VERSION 5.8 ;
BUSBITCHARS "[]" ;
DIVIDERCHAR "/" ;
UNITS
    DATABASE MICRONS 1000 ;
END UNITS

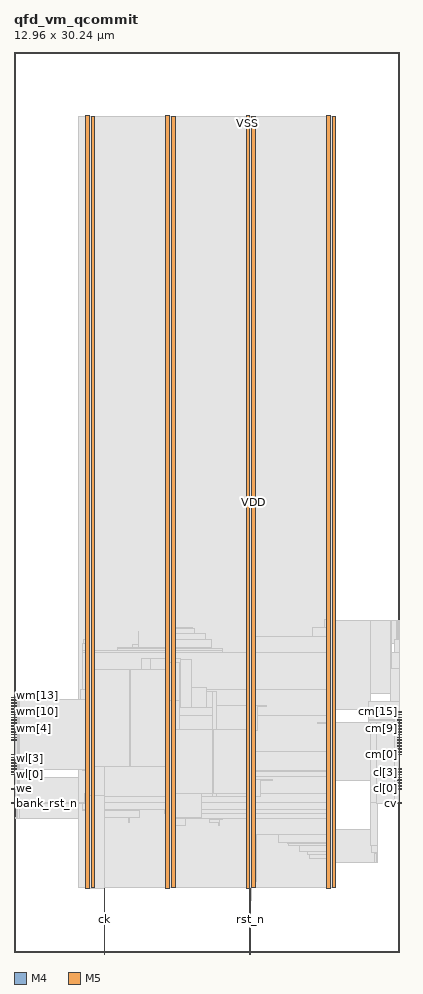
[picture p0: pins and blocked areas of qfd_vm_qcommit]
MACRO qfd_vm_qcommit
  FOREIGN qfd_vm_qcommit 0 0 ;
  CLASS BLOCK ;
  SIZE 12.96 BY 30.24 ;
  PIN bank_rst_n
    DIRECTION INPUT ;
    USE SIGNAL ;
    PORT
      LAYER M4 ;
        RECT  -0.072 4.992 0.072 5.016 ;
    END
  END bank_rst_n
  PIN ck
    DIRECTION INPUT ;
    USE SIGNAL ;
    PORT
      LAYER M5 ;
        RECT  3.024 -0.072 3.048 0.072 ;
    END
    PORT
      LAYER M5 ;
        RECT  3.024 0.016 3.048 2.137 ;
    END
  END ck
  PIN cl[0]
    DIRECTION OUTPUT ;
    USE SIGNAL ;
    PORT
      LAYER M4 ;
        RECT  12.888 5.472 13.032 5.496 ;
    END
  END cl[0]
  PIN cl[1]
    DIRECTION OUTPUT ;
    USE SIGNAL ;
    PORT
      LAYER M4 ;
        RECT  12.888 5.568 13.032 5.592 ;
    END
  END cl[1]
  PIN cl[2]
    DIRECTION OUTPUT ;
    USE SIGNAL ;
    PORT
      LAYER M4 ;
        RECT  12.888 5.664 13.032 5.688 ;
    END
  END cl[2]
  PIN cl[3]
    DIRECTION OUTPUT ;
    USE SIGNAL ;
    PORT
      LAYER M4 ;
        RECT  12.888 5.76 13.032 5.784 ;
    END
  END cl[3]
  PIN cl[4]
    DIRECTION OUTPUT ;
    USE SIGNAL ;
    PORT
      LAYER M4 ;
        RECT  12.888 5.856 13.032 5.88 ;
    END
  END cl[4]
  PIN cl[5]
    DIRECTION OUTPUT ;
    USE SIGNAL ;
    PORT
      LAYER M4 ;
        RECT  12.888 5.952 13.032 5.976 ;
    END
  END cl[5]
  PIN cl[6]
    DIRECTION OUTPUT ;
    USE SIGNAL ;
    PORT
      LAYER M4 ;
        RECT  12.888 6.048 13.032 6.072 ;
    END
  END cl[6]
  PIN cl[7]
    DIRECTION OUTPUT ;
    USE SIGNAL ;
    PORT
      LAYER M4 ;
        RECT  12.888 6.144 13.032 6.168 ;
    END
  END cl[7]
  PIN cm[0]
    DIRECTION OUTPUT ;
    USE SIGNAL ;
    PORT
      LAYER M4 ;
        RECT  12.888 6.624 13.032 6.648 ;
    END
  END cm[0]
  PIN cm[10]
    DIRECTION OUTPUT ;
    USE SIGNAL ;
    PORT
      LAYER M4 ;
        RECT  12.888 7.584 13.032 7.608 ;
    END
  END cm[10]
  PIN cm[11]
    DIRECTION OUTPUT ;
    USE SIGNAL ;
    PORT
      LAYER M4 ;
        RECT  12.888 7.68 13.032 7.704 ;
    END
  END cm[11]
  PIN cm[12]
    DIRECTION OUTPUT ;
    USE SIGNAL ;
    PORT
      LAYER M4 ;
        RECT  12.888 7.776 13.032 7.8 ;
    END
  END cm[12]
  PIN cm[13]
    DIRECTION OUTPUT ;
    USE SIGNAL ;
    PORT
      LAYER M4 ;
        RECT  12.888 7.872 13.032 7.896 ;
    END
  END cm[13]
  PIN cm[14]
    DIRECTION OUTPUT ;
    USE SIGNAL ;
    PORT
      LAYER M4 ;
        RECT  12.888 7.968 13.032 7.992 ;
    END
  END cm[14]
  PIN cm[15]
    DIRECTION OUTPUT ;
    USE SIGNAL ;
    PORT
      LAYER M4 ;
        RECT  12.888 8.064 13.032 8.088 ;
    END
  END cm[15]
  PIN cm[1]
    DIRECTION OUTPUT ;
    USE SIGNAL ;
    PORT
      LAYER M4 ;
        RECT  12.888 6.72 13.032 6.744 ;
    END
  END cm[1]
  PIN cm[2]
    DIRECTION OUTPUT ;
    USE SIGNAL ;
    PORT
      LAYER M4 ;
        RECT  12.888 6.816 13.032 6.84 ;
    END
  END cm[2]
  PIN cm[3]
    DIRECTION OUTPUT ;
    USE SIGNAL ;
    PORT
      LAYER M4 ;
        RECT  12.888 6.912 13.032 6.936 ;
    END
  END cm[3]
  PIN cm[4]
    DIRECTION OUTPUT ;
    USE SIGNAL ;
    PORT
      LAYER M4 ;
        RECT  12.888 7.008 13.032 7.032 ;
    END
  END cm[4]
  PIN cm[5]
    DIRECTION OUTPUT ;
    USE SIGNAL ;
    PORT
      LAYER M4 ;
        RECT  12.888 7.104 13.032 7.128 ;
    END
  END cm[5]
  PIN cm[6]
    DIRECTION OUTPUT ;
    USE SIGNAL ;
    PORT
      LAYER M4 ;
        RECT  12.888 7.2 13.032 7.224 ;
    END
  END cm[6]
  PIN cm[7]
    DIRECTION OUTPUT ;
    USE SIGNAL ;
    PORT
      LAYER M4 ;
        RECT  12.888 7.296 13.032 7.32 ;
    END
  END cm[7]
  PIN cm[8]
    DIRECTION OUTPUT ;
    USE SIGNAL ;
    PORT
      LAYER M4 ;
        RECT  12.888 7.392 13.032 7.416 ;
    END
  END cm[8]
  PIN cm[9]
    DIRECTION OUTPUT ;
    USE SIGNAL ;
    PORT
      LAYER M4 ;
        RECT  12.888 7.488 13.032 7.512 ;
    END
  END cm[9]
  PIN cv
    DIRECTION OUTPUT ;
    USE SIGNAL ;
    PORT
      LAYER M4 ;
        RECT  12.888 4.992 13.032 5.016 ;
    END
  END cv
  PIN rst_n
    DIRECTION INPUT ;
    USE SIGNAL ;
    PORT
      LAYER M5 ;
        RECT  7.92 -0.072 7.944 0.072 ;
    END
    PORT
      LAYER M5 ;
        RECT  7.92 0.016 7.944 2.137 ;
    END
  END rst_n
  PIN we
    DIRECTION INPUT ;
    USE SIGNAL ;
    PORT
      LAYER M4 ;
        RECT  -0.072 5.472 0.072 5.496 ;
    END
  END we
  PIN wl[0]
    DIRECTION INPUT ;
    USE SIGNAL ;
    PORT
      LAYER M4 ;
        RECT  -0.072 5.952 0.072 5.976 ;
    END
  END wl[0]
  PIN wl[1]
    DIRECTION INPUT ;
    USE SIGNAL ;
    PORT
      LAYER M4 ;
        RECT  -0.072 6.048 0.072 6.072 ;
    END
  END wl[1]
  PIN wl[2]
    DIRECTION INPUT ;
    USE SIGNAL ;
    PORT
      LAYER M4 ;
        RECT  -0.072 6.144 0.072 6.168 ;
    END
  END wl[2]
  PIN wl[3]
    DIRECTION INPUT ;
    USE SIGNAL ;
    PORT
      LAYER M4 ;
        RECT  -0.072 6.24 0.072 6.264 ;
    END
  END wl[3]
  PIN wl[4]
    DIRECTION INPUT ;
    USE SIGNAL ;
    PORT
      LAYER M4 ;
        RECT  -0.072 6.336 0.072 6.36 ;
    END
  END wl[4]
  PIN wl[5]
    DIRECTION INPUT ;
    USE SIGNAL ;
    PORT
      LAYER M4 ;
        RECT  -0.072 6.432 0.072 6.456 ;
    END
  END wl[5]
  PIN wl[6]
    DIRECTION INPUT ;
    USE SIGNAL ;
    PORT
      LAYER M4 ;
        RECT  -0.072 6.528 0.072 6.552 ;
    END
  END wl[6]
  PIN wl[7]
    DIRECTION INPUT ;
    USE SIGNAL ;
    PORT
      LAYER M4 ;
        RECT  -0.072 6.624 0.072 6.648 ;
    END
  END wl[7]
  PIN wm[0]
    DIRECTION INPUT ;
    USE SIGNAL ;
    PORT
      LAYER M4 ;
        RECT  -0.072 7.104 0.072 7.128 ;
    END
  END wm[0]
  PIN wm[10]
    DIRECTION INPUT ;
    USE SIGNAL ;
    PORT
      LAYER M4 ;
        RECT  -0.072 8.064 0.072 8.088 ;
    END
  END wm[10]
  PIN wm[11]
    DIRECTION INPUT ;
    USE SIGNAL ;
    PORT
      LAYER M4 ;
        RECT  -0.072 8.16 0.072 8.184 ;
    END
  END wm[11]
  PIN wm[12]
    DIRECTION INPUT ;
    USE SIGNAL ;
    PORT
      LAYER M4 ;
        RECT  -0.072 8.256 0.072 8.28 ;
    END
  END wm[12]
  PIN wm[13]
    DIRECTION INPUT ;
    USE SIGNAL ;
    PORT
      LAYER M4 ;
        RECT  -0.072 8.352 0.072 8.376 ;
    END
  END wm[13]
  PIN wm[14]
    DIRECTION INPUT ;
    USE SIGNAL ;
    PORT
      LAYER M4 ;
        RECT  -0.072 8.448 0.072 8.472 ;
    END
  END wm[14]
  PIN wm[15]
    DIRECTION INPUT ;
    USE SIGNAL ;
    PORT
      LAYER M4 ;
        RECT  -0.072 8.544 0.072 8.568 ;
    END
  END wm[15]
  PIN wm[1]
    DIRECTION INPUT ;
    USE SIGNAL ;
    PORT
      LAYER M4 ;
        RECT  -0.072 7.2 0.072 7.224 ;
    END
  END wm[1]
  PIN wm[2]
    DIRECTION INPUT ;
    USE SIGNAL ;
    PORT
      LAYER M4 ;
        RECT  -0.072 7.296 0.072 7.32 ;
    END
  END wm[2]
  PIN wm[3]
    DIRECTION INPUT ;
    USE SIGNAL ;
    PORT
      LAYER M4 ;
        RECT  -0.072 7.392 0.072 7.416 ;
    END
  END wm[3]
  PIN wm[4]
    DIRECTION INPUT ;
    USE SIGNAL ;
    PORT
      LAYER M4 ;
        RECT  -0.072 7.488 0.072 7.512 ;
    END
  END wm[4]
  PIN wm[5]
    DIRECTION INPUT ;
    USE SIGNAL ;
    PORT
      LAYER M4 ;
        RECT  -0.072 7.584 0.072 7.608 ;
    END
  END wm[5]
  PIN wm[6]
    DIRECTION INPUT ;
    USE SIGNAL ;
    PORT
      LAYER M4 ;
        RECT  -0.072 7.68 0.072 7.704 ;
    END
  END wm[6]
  PIN wm[7]
    DIRECTION INPUT ;
    USE SIGNAL ;
    PORT
      LAYER M4 ;
        RECT  -0.072 7.776 0.072 7.8 ;
    END
  END wm[7]
  PIN wm[8]
    DIRECTION INPUT ;
    USE SIGNAL ;
    PORT
      LAYER M4 ;
        RECT  -0.072 7.872 0.072 7.896 ;
    END
  END wm[8]
  PIN wm[9]
    DIRECTION INPUT ;
    USE SIGNAL ;
    PORT
      LAYER M4 ;
        RECT  -0.072 7.968 0.072 7.992 ;
    END
  END wm[9]
  PIN VDD
    DIRECTION INOUT ;
    USE POWER ;
    PORT
      LAYER M5 ;
        RECT  10.692 2.151 10.812 28.089 ;
        RECT  7.992 2.151 8.112 28.089 ;
        RECT  5.292 2.151 5.412 28.089 ;
        RECT  2.592 2.151 2.712 28.089 ;
    END
  END VDD
  PIN VSS
    DIRECTION INOUT ;
    USE GROUND ;
    PORT
      LAYER M5 ;
        RECT  10.5 2.137 10.62 28.103 ;
        RECT  7.8 2.137 7.92 28.103 ;
        RECT  5.1 2.137 5.22 28.103 ;
        RECT  2.4 2.137 2.52 28.103 ;
    END
  END VSS
  # OT_OBS_CLOSED layer=M5 d_um=1.536 added=6
  OBS
    LAYER RVTN ;
     RECT  2.16 2.16 10.8 2.295 ;
     RECT  2.16 2.565 10.8 2.835 ;
     RECT  2.16 3.105 10.8 3.375 ;
     RECT  2.16 3.645 10.8 3.915 ;
     RECT  2.16 4.185 10.8 4.455 ;
     RECT  2.16 4.725 10.8 4.995 ;
     RECT  2.16 5.265 10.8 5.535 ;
     RECT  2.16 5.805 10.8 6.075 ;
     RECT  2.16 6.345 10.8 6.615 ;
     RECT  2.16 6.885 10.8 7.155 ;
     RECT  2.16 7.425 10.8 7.695 ;
     RECT  2.16 7.965 10.8 8.235 ;
     RECT  2.16 8.505 10.8 8.775 ;
     RECT  2.16 9.045 10.8 9.315 ;
     RECT  2.16 9.585 10.8 9.855 ;
     RECT  2.16 10.125 10.8 10.395 ;
     RECT  2.16 10.665 10.8 10.935 ;
     RECT  2.16 11.205 10.8 11.475 ;
     RECT  2.16 11.745 10.8 12.015 ;
     RECT  2.16 12.285 10.8 12.555 ;
     RECT  2.16 12.825 10.8 13.095 ;
     RECT  2.16 13.365 10.8 13.635 ;
     RECT  2.16 13.905 10.8 14.175 ;
     RECT  2.16 14.445 10.8 14.715 ;
     RECT  2.16 14.985 10.8 15.255 ;
     RECT  2.16 15.525 10.8 15.795 ;
     RECT  2.16 16.065 10.8 16.335 ;
     RECT  2.16 16.605 10.8 16.875 ;
     RECT  2.16 17.145 10.8 17.415 ;
     RECT  2.16 17.685 10.8 17.955 ;
     RECT  2.16 18.225 10.8 18.495 ;
     RECT  2.16 18.765 10.8 19.035 ;
     RECT  2.16 19.305 10.8 19.575 ;
     RECT  2.16 19.845 10.8 20.115 ;
     RECT  2.16 20.385 10.8 20.655 ;
     RECT  2.16 20.925 10.8 21.195 ;
     RECT  2.16 21.465 10.8 21.735 ;
     RECT  2.16 22.005 10.8 22.275 ;
     RECT  2.16 22.545 10.8 22.815 ;
     RECT  2.16 23.085 10.8 23.355 ;
     RECT  2.16 23.625 10.8 23.895 ;
     RECT  2.16 24.165 10.8 24.435 ;
     RECT  2.16 24.705 10.8 24.975 ;
     RECT  2.16 25.245 10.8 25.515 ;
     RECT  2.16 25.785 10.8 26.055 ;
     RECT  2.16 26.325 10.8 26.595 ;
     RECT  2.16 26.865 10.8 27.135 ;
     RECT  2.16 27.405 10.8 27.675 ;
     RECT  2.16 27.945 10.8 28.08 ;
    LAYER RVTP ;
     RECT  2.16 2.295 10.8 2.565 ;
     RECT  2.16 2.835 10.8 3.105 ;
     RECT  2.16 3.375 10.8 3.645 ;
     RECT  2.16 3.915 10.8 4.185 ;
     RECT  2.16 4.455 10.8 4.725 ;
     RECT  2.16 4.995 10.8 5.265 ;
     RECT  2.16 5.535 10.8 5.805 ;
     RECT  2.16 6.075 10.8 6.345 ;
     RECT  2.16 6.615 10.8 6.885 ;
     RECT  2.16 7.155 10.8 7.425 ;
     RECT  2.16 7.695 10.8 7.965 ;
     RECT  2.16 8.235 10.8 8.505 ;
     RECT  2.16 8.775 10.8 9.045 ;
     RECT  2.16 9.315 10.8 9.585 ;
     RECT  2.16 9.855 10.8 10.125 ;
     RECT  2.16 10.395 10.8 10.665 ;
     RECT  2.16 10.935 10.8 11.205 ;
     RECT  2.16 11.475 10.8 11.745 ;
     RECT  2.16 12.015 10.8 12.285 ;
     RECT  2.16 12.555 10.8 12.825 ;
     RECT  2.16 13.095 10.8 13.365 ;
     RECT  2.16 13.635 10.8 13.905 ;
     RECT  2.16 14.175 10.8 14.445 ;
     RECT  2.16 14.715 10.8 14.985 ;
     RECT  2.16 15.255 10.8 15.525 ;
     RECT  2.16 15.795 10.8 16.065 ;
     RECT  2.16 16.335 10.8 16.605 ;
     RECT  2.16 16.875 10.8 17.145 ;
     RECT  2.16 17.415 10.8 17.685 ;
     RECT  2.16 17.955 10.8 18.225 ;
     RECT  2.16 18.495 10.8 18.765 ;
     RECT  2.16 19.035 10.8 19.305 ;
     RECT  2.16 19.575 10.8 19.845 ;
     RECT  2.16 20.115 10.8 20.385 ;
     RECT  2.16 20.655 10.8 20.925 ;
     RECT  2.16 21.195 10.8 21.465 ;
     RECT  2.16 21.735 10.8 22.005 ;
     RECT  2.16 22.275 10.8 22.545 ;
     RECT  2.16 22.815 10.8 23.085 ;
     RECT  2.16 23.355 10.8 23.625 ;
     RECT  2.16 23.895 10.8 24.165 ;
     RECT  2.16 24.435 10.8 24.705 ;
     RECT  2.16 24.975 10.8 25.245 ;
     RECT  2.16 25.515 10.8 25.785 ;
     RECT  2.16 26.055 10.8 26.325 ;
     RECT  2.16 26.595 10.8 26.865 ;
     RECT  2.16 27.135 10.8 27.405 ;
     RECT  2.16 27.675 10.8 27.945 ;
    LAYER M1 ;
     RECT  2.16 2.151 10.8 28.089 ;
    LAYER M2 ;
     RECT  0.067 4.5 0.103 4.518 ;
     RECT  0.067 5.58 0.103 5.598 ;
     RECT  0.067 6.822 0.103 6.84 ;
     RECT  0.103 4.5 0.175 5.598 ;
     RECT  0.175 4.5 2.16 5.868 ;
     RECT  0.103 6.822 2.16 7.416 ;
     RECT  0.067 8.442 2.16 8.46 ;
     RECT  2.16 2.151 10.8 28.089 ;
     RECT  10.8 2.421 10.812 27.819 ;
     RECT  10.812 5.886 11.435 7.344 ;
     RECT  11.435 5.976 11.975 7.344 ;
     RECT  10.812 8.136 11.975 11.124 ;
     RECT  11.975 5.976 12.011 6.714 ;
     RECT  12.011 6.552 12.083 6.714 ;
     RECT  10.812 3.006 12.119 4.104 ;
     RECT  12.119 4.086 12.155 4.104 ;
     RECT  12.119 3.006 12.191 3.294 ;
     RECT  12.191 3.006 12.227 3.024 ;
     RECT  11.975 8.676 12.659 11.124 ;
     RECT  12.659 10.026 12.695 11.124 ;
     RECT  12.659 8.676 12.731 8.964 ;
     RECT  12.731 8.946 12.767 8.964 ;
     RECT  12.695 10.368 12.839 11.124 ;
     RECT  12.839 10.44 12.875 11.124 ;
     RECT  12.847 7.821 12.947 7.839 ;
     RECT  12.875 11.106 12.947 11.124 ;
    LAYER M3 ;
     RECT  7.956 1.723 7.974 2.143 ;
     RECT  7.815 2.143 7.974 2.371 ;
     RECT  2.415 2.143 2.505 2.413 ;
     RECT  5.115 2.143 5.205 2.413 ;
     RECT  10.515 2.143 10.605 2.413 ;
     RECT  10.515 2.413 10.797 3.145 ;
     RECT  9.936 3.145 10.797 3.271 ;
     RECT  12.204 3.001 12.222 3.271 ;
     RECT  12.168 3.271 12.222 3.343 ;
     RECT  9.864 3.271 10.797 3.379 ;
     RECT  9.576 3.379 10.797 3.577 ;
     RECT  12.024 3.343 12.222 3.577 ;
     RECT  9.216 3.577 10.797 3.649 ;
     RECT  9.18 3.649 10.797 3.685 ;
     RECT  7.815 2.371 8.154 3.955 ;
     RECT  8.892 3.685 10.797 3.955 ;
     RECT  5.115 2.413 5.397 4.261 ;
     RECT  6.876 4.261 6.894 4.351 ;
     RECT  6.552 4.351 6.894 4.459 ;
     RECT  5.115 4.261 5.778 4.495 ;
     RECT  6.552 4.459 7.002 4.495 ;
     RECT  7.815 3.955 10.797 4.495 ;
     RECT  2.415 2.413 2.697 4.531 ;
     RECT  3.852 4.351 3.87 4.531 ;
     RECT  5.115 4.495 10.797 4.657 ;
     RECT  2.415 4.531 4.23 4.765 ;
     RECT  2.304 4.765 4.23 4.801 ;
     RECT  5.04 4.657 10.797 4.801 ;
     RECT  2.304 4.801 10.797 5.021 ;
     RECT  11.988 3.577 12.222 5.021 ;
     RECT  0.072 4.495 0.09 5.035 ;
     RECT  2.376 5.021 10.797 5.333 ;
     RECT  0.072 5.035 0.162 5.845 ;
     RECT  2.415 5.333 10.797 5.881 ;
     RECT  11.988 5.021 12.186 5.881 ;
     RECT  2.415 5.881 12.186 6.077 ;
     RECT  2.415 6.077 12.078 6.115 ;
     RECT  0.072 5.845 0.198 6.557 ;
     RECT  2.304 6.115 12.078 6.749 ;
     RECT  11.916 6.749 12.078 7.099 ;
     RECT  0.072 6.557 0.09 7.393 ;
     RECT  0.072 7.393 0.126 7.421 ;
     RECT  0.108 7.421 0.126 7.613 ;
     RECT  11.916 7.099 12.762 7.771 ;
     RECT  11.916 7.771 12.87 7.816 ;
     RECT  2.304 6.749 10.797 7.963 ;
     RECT  11.916 7.816 12.942 8.429 ;
     RECT  0.072 8.437 0.09 8.573 ;
     RECT  2.232 7.963 10.797 8.807 ;
     RECT  12.636 8.429 12.942 9.509 ;
     RECT  2.304 8.807 10.797 10.049 ;
     RECT  12.672 9.509 12.942 10.049 ;
     RECT  2.304 10.049 7.002 10.121 ;
     RECT  3.492 10.121 7.002 10.193 ;
     RECT  3.492 10.193 6.642 10.229 ;
     RECT  3.996 10.229 4.194 10.319 ;
     RECT  2.304 10.121 2.697 10.355 ;
     RECT  2.34 10.355 2.697 10.499 ;
     RECT  5.115 10.229 6.642 10.499 ;
     RECT  12.78 10.049 12.942 10.499 ;
     RECT  7.815 10.049 10.797 10.589 ;
     RECT  5.115 10.499 6.426 10.697 ;
     RECT  4.176 10.319 4.194 10.769 ;
     RECT  5.115 10.697 6.066 10.859 ;
     RECT  5.115 10.859 5.994 10.895 ;
     RECT  10.044 10.589 10.797 10.895 ;
     RECT  12.924 10.499 12.942 11.129 ;
     RECT  10.44 10.895 10.797 11.165 ;
     RECT  2.415 10.499 2.697 27.827 ;
     RECT  5.115 10.895 5.397 27.827 ;
     RECT  7.815 10.589 8.097 27.827 ;
     RECT  10.515 11.165 10.797 27.827 ;
     RECT  2.415 27.827 2.505 28.097 ;
     RECT  5.115 27.827 5.205 28.097 ;
     RECT  7.815 27.827 7.905 28.097 ;
     RECT  10.515 27.827 10.605 28.097 ;
    LAYER M4 ;
     RECT  0.06 4.992 0.101 8.568 ;
     RECT  0.101 4.992 0.137 8.472 ;
     RECT  0.137 6.048 0.173 8.472 ;
     RECT  0.137 4.992 2.408 5.016 ;
     RECT  0.173 6.144 2.408 8.472 ;
     RECT  2.408 2.148 2.512 28.092 ;
     RECT  2.512 2.418 2.704 27.822 ;
     RECT  2.704 8.256 2.837 8.28 ;
     RECT  3.733 9.456 4.057 9.48 ;
     RECT  4.057 9.12 4.273 9.48 ;
     RECT  4.273 9.12 4.597 9.864 ;
     RECT  2.704 5.232 5.108 7.128 ;
     RECT  4.597 8.736 5.108 9.864 ;
     RECT  5.108 2.148 5.212 28.092 ;
     RECT  5.212 2.418 5.404 27.822 ;
     RECT  5.404 8.208 5.609 9.864 ;
     RECT  5.609 8.208 5.969 9.816 ;
     RECT  5.404 4.512 6.293 7.224 ;
     RECT  5.969 8.208 6.473 8.904 ;
     RECT  6.293 5.232 6.661 7.224 ;
     RECT  6.473 8.208 6.661 8.76 ;
     RECT  6.661 5.232 6.797 8.76 ;
     RECT  6.797 5.232 7.808 8.28 ;
     RECT  7.808 2.148 7.901 28.092 ;
     RECT  7.901 1.728 7.912 28.092 ;
     RECT  7.912 1.728 7.985 27.822 ;
     RECT  7.985 2.418 8.104 27.822 ;
     RECT  8.104 7.44 8.165 8.28 ;
     RECT  8.104 5.232 8.273 5.784 ;
     RECT  8.165 8.256 8.489 8.28 ;
     RECT  8.273 5.76 8.669 5.784 ;
     RECT  10.213 7.68 10.508 7.704 ;
     RECT  10.508 2.148 10.612 28.092 ;
     RECT  10.612 2.418 10.804 27.822 ;
     RECT  10.804 5.76 11.977 7.704 ;
     RECT  11.977 5.472 12.193 7.704 ;
     RECT  12.193 4.992 12.769 7.704 ;
     RECT  12.769 4.992 12.924 8.088 ;
    LAYER M5 ;
     RECT  5.1 2.137 5.22 2.151 ;
     RECT  7.8 2.137 7.944 2.151 ;
     RECT  10.5 2.137 10.62 2.151 ;
     RECT  2.4 2.137 3.048 5.267 ;
     RECT  6.672 5.317 6.696 7.475 ;
     RECT  5.1 2.151 5.412 8.437 ;
     RECT  3.888 6.229 3.912 9.491 ;
     RECT  5.1 8.437 5.544 9.731 ;
     RECT  2.4 5.267 2.712 28.089 ;
     RECT  5.1 9.731 5.412 28.089 ;
     RECT  7.8 2.151 8.112 28.089 ;
     RECT  10.5 2.151 10.812 28.089 ;
     RECT  2.4 28.089 2.52 28.103 ;
     RECT  5.1 28.089 5.22 28.103 ;
     RECT  7.8 28.089 7.92 28.103 ;
     RECT  10.5 28.089 10.62 28.103 ;
     RECT  2.712 5.267 3.048 6.229 ;
     RECT  5.412 5.317 6.672 7.475 ;
     RECT  6.696 5.317 7.8 7.475 ;
     RECT  2.712 6.229 3.888 9.491 ;
     RECT  3.912 6.229 5.1 9.491 ;
     RECT  5.412 7.475 5.544 8.437 ;
  END
END qfd_vm_qcommit
END LIBRARY
